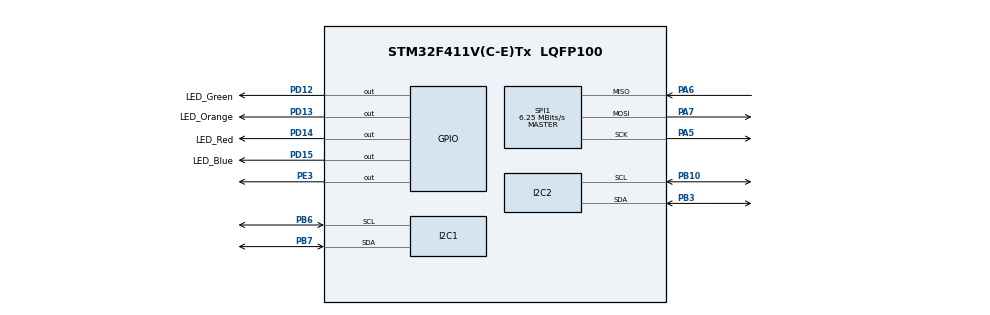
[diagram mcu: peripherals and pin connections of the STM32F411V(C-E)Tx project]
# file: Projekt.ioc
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Mcu.Family=STM32F4
Mcu.Name=STM32F411V(C-E)Tx
Mcu.Package=LQFP100
NVIC.PriorityGroup=NVIC_PRIORITYGROUP_4
PA5.Mode=Full_Duplex_Master
PA5.Signal=SPI1_SCK
PA6.Mode=Full_Duplex_Master
PA6.Signal=SPI1_MISO
PA7.Mode=Full_Duplex_Master
PA7.Signal=SPI1_MOSI
PB10.Mode=I2C
PB10.Signal=I2C2_SCL
PB3.Mode=I2C
PB3.Signal=I2C2_SDA
PB6.Mode=I2C
PB6.Signal=I2C1_SCL
PB7.Mode=I2C
PB7.Signal=I2C1_SDA
PD12.GPIO_Label=LED_Green
PD12.Signal=GPIO_Output
PD13.GPIO_Label=LED_Orange
PD13.Signal=GPIO_Output
PD14.GPIO_Label=LED_Red
PD14.Signal=GPIO_Output
PD15.GPIO_Label=LED_Blue
PD15.Signal=GPIO_Output
PE3.Signal=GPIO_Output
ProjectManager.HeapSize=0x200
ProjectManager.StackSize=0x400
ProjectManager.TargetToolchain=STM32CubeIDE
RCC.48MHZClocksFreq_Value=50000000
RCC.AHBFreq_Value=100000000
RCC.APB1CLKDivider=RCC_HCLK_DIV2
RCC.APB1Freq_Value=50000000
RCC.APB1TimFreq_Value=100000000
RCC.APB2Freq_Value=100000000
RCC.APB2TimFreq_Value=100000000
RCC.CortexFreq_Value=100000000
RCC.HCLKFreq_Value=100000000
RCC.HSE_VALUE=25000000
RCC.HSI_VALUE=16000000
RCC.LSE_VALUE=32768
RCC.PLLM=8
RCC.PLLN=100
RCC.SYSCLKFreq_VALUE=100000000
RCC.SYSCLKSource=RCC_SYSCLKSOURCE_PLLCLK
RCC.VCOOutputFreq_Value=200000000
SPI1.BaudRatePrescaler=SPI_BAUDRATEPRESCALER_16
SPI1.CalculateBaudRate=6.25 MBits/s
SPI1.Direction=SPI_DIRECTION_2LINES
SPI1.Mode=SPI_MODE_MASTER
SPI1.VirtualType=VM_MASTER
board=custom

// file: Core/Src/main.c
/* USER CODE BEGIN Header */
/**
  ******************************************************************************
  * @file           : main.c
  * @brief          : Main program body
  ******************************************************************************
  * @attention
  *
  * Copyright (c) 2022 STMicroelectronics.
  * All rights reserved.
  *
  * This software is licensed under terms that can be found in the LICENSE file
  * in the root directory of this software component.
  * If no LICENSE file comes with this software, it is provided AS-IS.
  *
  ******************************************************************************
  */
/* USER CODE END Header */
#include "main.h"

/* USER CODE BEGIN Includes */
#include <stdlib.h>
#include<stdio.h>
#include "../../../Drivers/BSP/STM32F411E-Discovery/stm32f411e_discovery.h"
#include "../../../Drivers/BSP/STM32F411E-Discovery/stm32f411e_discovery_gyroscope.h"
#include "ssd1306.h"
#include "fonts.h"
/* USER CODE END Includes */

I2C_HandleTypeDef hi2c1;
I2C_HandleTypeDef hi2c2;

SPI_HandleTypeDef hspi1;

void SystemClock_Config(void);
static void MX_GPIO_Init(void);
static void MX_I2C1_Init(void);
static void MX_I2C2_Init(void);
static void MX_SPI1_Init(void);

int main(void)
{

  /* MCU Configuration--------------------------------------------------------*/

  /* Reset of all peripherals, Initializes the Flash interface and the Systick. */
  HAL_Init();

  /* Configure the system clock */
  SystemClock_Config();

  /* Initialize all configured peripherals */
  MX_GPIO_Init();
  MX_I2C1_Init();
  MX_I2C2_Init();
  MX_SPI1_Init();
  /* USER CODE BEGIN 2 */
  BSP_GYRO_Init();
  ssd1306_Init(&hi2c2);

  float axis[3];
  float xAxis, yAxis = 0.0f;
  float axisTreshold = 10000.0f;
  uint32_t delayMs = 20;

  float xAxisDisplay = 0.0f;
  float yAxisDisplay = 0.0f;

  char xText[16];
  char yText[16];

  void turnOnLed(GPIO_TypeDef* GPIOx, uint16_t GPIO_Pin)
  {
	HAL_GPIO_WritePin(GPIOx, GPIO_Pin, GPIO_PIN_SET);
	HAL_Delay(delayMs);
  }

  void turnOfLEDS()
  {
	HAL_GPIO_WritePin(LED_Green_GPIO_Port, LED_Green_Pin, GPIO_PIN_RESET);
	HAL_GPIO_WritePin(LED_Red_GPIO_Port, LED_Red_Pin, GPIO_PIN_RESET);
	HAL_GPIO_WritePin(LED_Orange_GPIO_Port, LED_Orange_Pin, GPIO_PIN_RESET);
	HAL_GPIO_WritePin(LED_Blue_GPIO_Port, LED_Blue_Pin, GPIO_PIN_RESET);
  }
  /* USER CODE END 2 */

  /* Infinite loop */
  while (1)
    {

      /* USER CODE BEGIN 3 */
  	  BSP_GYRO_GetXYZ(axis);

  	  ssd1306_Fill(Black);

  	  	xAxis = abs((axis[0]));
  	  	yAxis = abs((axis[1]));

  	  	xAxisDisplay = axis[0] / axisTreshold;
  	  	yAxisDisplay = axis[1] / axisTreshold;

  	  	if(xAxis > yAxis)
  	  	{
  	  	  if(axis[0] > axisTreshold)
  	  		  turnOnLed(LED_Green_GPIO_Port, LED_Green_Pin);

  	  	  else if(axis[0] < -axisTreshold)
  	  		  turnOnLed(LED_Red_GPIO_Port, LED_Red_Pin);

  	  	  else { HAL_Delay(delayMs); }
  	  	}

  	  	else
  	  	{
  	  	  if(axis[1] < -axisTreshold)
  	  		  turnOnLed(LED_Orange_GPIO_Port, LED_Orange_Pin);

  	  	  else if(axis[1] > axisTreshold)
  	  		  turnOnLed(LED_Blue_GPIO_Port, LED_Blue_Pin);

  	  	  else { HAL_Delay(delayMs); }
  	  	}

  	  	ssd1306_SetCursor(10, 10);
  	  	sprintf(xText, "x: %.2f", xAxisDisplay);
  		ssd1306_WriteString(xText, Font_11x18, White);

  	  	ssd1306_SetCursor(10, 40);
  	  	sprintf(yText, "y: %.2f", yAxisDisplay);
  	  	ssd1306_WriteString(yText, Font_11x18, White);

  	  	ssd1306_UpdateScreen(&hi2c2);

  	  	turnOfLEDS();
    }
  /* USER CODE END 3 */
}

void SystemClock_Config(void)
{
  RCC_OscInitTypeDef RCC_OscInitStruct = {0};
  RCC_ClkInitTypeDef RCC_ClkInitStruct = {0};

  /** Configure the main internal regulator output voltage
  */
  __HAL_RCC_PWR_CLK_ENABLE();
  __HAL_PWR_VOLTAGESCALING_CONFIG(PWR_REGULATOR_VOLTAGE_SCALE1);

  /** Initializes the RCC Oscillators according to the specified parameters
  * in the RCC_OscInitTypeDef structure.
  */
  RCC_OscInitStruct.OscillatorType = RCC_OSCILLATORTYPE_HSI;
  RCC_OscInitStruct.HSIState = RCC_HSI_ON;
  RCC_OscInitStruct.HSICalibrationValue = RCC_HSICALIBRATION_DEFAULT;
  RCC_OscInitStruct.PLL.PLLState = RCC_PLL_ON;
  RCC_OscInitStruct.PLL.PLLSource = RCC_PLLSOURCE_HSI;
  RCC_OscInitStruct.PLL.PLLM = 8;
  RCC_OscInitStruct.PLL.PLLN = 100;
  RCC_OscInitStruct.PLL.PLLP = RCC_PLLP_DIV2;
  RCC_OscInitStruct.PLL.PLLQ = 8;
  if (HAL_RCC_OscConfig(&RCC_OscInitStruct) != HAL_OK)
  {
    Error_Handler();
  }

  /** Initializes the CPU, AHB and APB buses clocks
  */
  RCC_ClkInitStruct.ClockType = RCC_CLOCKTYPE_HCLK|RCC_CLOCKTYPE_SYSCLK
                              |RCC_CLOCKTYPE_PCLK1|RCC_CLOCKTYPE_PCLK2;
  RCC_ClkInitStruct.SYSCLKSource = RCC_SYSCLKSOURCE_PLLCLK;
  RCC_ClkInitStruct.AHBCLKDivider = RCC_SYSCLK_DIV1;
  RCC_ClkInitStruct.APB1CLKDivider = RCC_HCLK_DIV2;
  RCC_ClkInitStruct.APB2CLKDivider = RCC_HCLK_DIV2;

  if (HAL_RCC_ClockConfig(&RCC_ClkInitStruct, FLASH_LATENCY_3) != HAL_OK)
  {
    Error_Handler();
  }
}

static void MX_I2C1_Init(void)
{

  hi2c1.Instance = I2C1;
  hi2c1.Init.ClockSpeed = 100000;
  hi2c1.Init.DutyCycle = I2C_DUTYCYCLE_2;
  hi2c1.Init.OwnAddress1 = 0;
  hi2c1.Init.AddressingMode = I2C_ADDRESSINGMODE_7BIT;
  hi2c1.Init.DualAddressMode = I2C_DUALADDRESS_DISABLE;
  hi2c1.Init.OwnAddress2 = 0;
  hi2c1.Init.GeneralCallMode = I2C_GENERALCALL_DISABLE;
  hi2c1.Init.NoStretchMode = I2C_NOSTRETCH_DISABLE;
  if (HAL_I2C_Init(&hi2c1) != HAL_OK)
  {
    Error_Handler();
  }

}

static void MX_I2C2_Init(void)
{

  hi2c2.Instance = I2C2;
  hi2c2.Init.ClockSpeed = 100000;
  hi2c2.Init.DutyCycle = I2C_DUTYCYCLE_2;
  hi2c2.Init.OwnAddress1 = 0;
  hi2c2.Init.AddressingMode = I2C_ADDRESSINGMODE_7BIT;
  hi2c2.Init.DualAddressMode = I2C_DUALADDRESS_DISABLE;
  hi2c2.Init.OwnAddress2 = 0;
  hi2c2.Init.GeneralCallMode = I2C_GENERALCALL_DISABLE;
  hi2c2.Init.NoStretchMode = I2C_NOSTRETCH_DISABLE;
  if (HAL_I2C_Init(&hi2c2) != HAL_OK)
  {
    Error_Handler();
  }

}

static void MX_SPI1_Init(void)
{

  /* SPI1 parameter configuration*/
  hspi1.Instance = SPI1;
  hspi1.Init.Mode = SPI_MODE_MASTER;
  hspi1.Init.Direction = SPI_DIRECTION_2LINES;
  hspi1.Init.DataSize = SPI_DATASIZE_8BIT;
  hspi1.Init.CLKPolarity = SPI_POLARITY_LOW;
  hspi1.Init.CLKPhase = SPI_PHASE_1EDGE;
  hspi1.Init.NSS = SPI_NSS_SOFT;
  hspi1.Init.BaudRatePrescaler = SPI_BAUDRATEPRESCALER_8;
  hspi1.Init.FirstBit = SPI_FIRSTBIT_MSB;
  hspi1.Init.TIMode = SPI_TIMODE_DISABLE;
  hspi1.Init.CRCCalculation = SPI_CRCCALCULATION_DISABLE;
  hspi1.Init.CRCPolynomial = 10;
  if (HAL_SPI_Init(&hspi1) != HAL_OK)
  {
    Error_Handler();
  }

}

static void MX_GPIO_Init(void)
{
  GPIO_InitTypeDef GPIO_InitStruct = {0};

  /* GPIO Ports Clock Enable */
  __HAL_RCC_GPIOA_CLK_ENABLE();
  __HAL_RCC_GPIOB_CLK_ENABLE();
  __HAL_RCC_GPIOD_CLK_ENABLE();

  /*Configure GPIO pin Output Level */
  HAL_GPIO_WritePin(GPIOD, LED_Green_Pin|LED_Orange_Pin|LED_Red_Pin|LED_Blue_Pin, GPIO_PIN_RESET);

  /*Configure GPIO pins : LED_Green_Pin LED_Orange_Pin LED_Red_Pin LED_Blue_Pin */
  GPIO_InitStruct.Pin = LED_Green_Pin|LED_Orange_Pin|LED_Red_Pin|LED_Blue_Pin;
  GPIO_InitStruct.Mode = GPIO_MODE_OUTPUT_PP;
  GPIO_InitStruct.Pull = GPIO_NOPULL;
  GPIO_InitStruct.Speed = GPIO_SPEED_FREQ_LOW;
  HAL_GPIO_Init(GPIOD, &GPIO_InitStruct);

}

void Error_Handler(void)
{
  __disable_irq();
  while (1)
  {
  }
}
